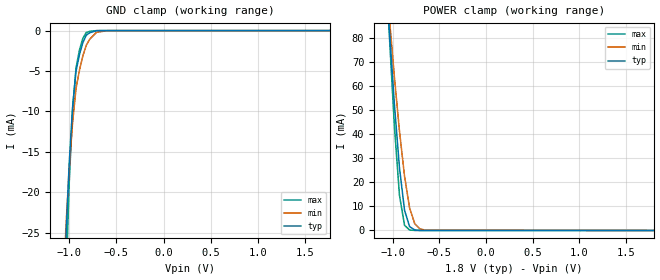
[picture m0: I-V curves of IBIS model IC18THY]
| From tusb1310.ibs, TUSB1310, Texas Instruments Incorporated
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|   Model Cell IC18THY_10P
[Model]   IC18THY
Model_type   Input
Polarity   Non-Inverting
Vinl =  0.63
Vinh =  1.17
C_comp   0.6387869p   0.5449568p   0.7565208p
[Model Spec]
Vinl   0.63   0.567   0.693
Vinh   1.17   1.053   1.287
[Temperature Range]   25   125   -40
[Voltage Range]   1.8   1.62   1.98
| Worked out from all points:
|   GND clamp passes 1 mA (typ) near -0.84 V on its own axis
|   POWER clamp passes 1 mA (typ) near -0.79 V on its own axis
[POWER_clamp]
|   voltage   I(typ)   I(min)   I(max)
-1.8V     607mA      492.8mA    733.5mA
-1.055V   94.75mA    97.21mA    95.13mA
-1.036V   83.56mA    88.51mA    81.22mA
-981.8mV  52.51mA    63.81mA    43.47mA
-927.3mV  26.09mA    41.33mA    14.63mA
-872.7mV  8.397mA    22.47mA    2.133mA
-818.2mV  1.587mA    9.312mA    180.8uA
-763.6mV  228.2uA    2.824mA    13.3uA
-709.1mV  29.94uA    699.1uA    954.3nA
-654.5mV  3.826uA    158.9uA    68.55nA
1.8V      3.537pA    1.237pA    21.97pA
[GND_clamp]
|   voltage   I(typ)   I(min)   I(max)
-1.8V     -539.1mA   -380.2mA   -748.9mA
-1.036V   -26.23mA   -24.68mA   -32.15mA
-1V       -16.52mA   -17.21mA   -19.02mA
-963.6mV  -9.451mA   -11.37mA   -9.842mA
-927.3mV  -5.032mA   -7.151mA   -4.619mA
-890.9mV  -2.977mA   -4.906mA   -2.412mA
-854.5mV  -1.487mA   -3.125mA   -949.1uA
-818.2mV  -563.1uA   -1.808mA   -231uA
-781.8mV  -269.9uA   -1.064mA   -91.31uA
-709.1mV  -19.12uA   -213.6uA   -1.454uA
-600mV    -278.7nA   -13.18uA   -7.254nA
1.764V    3.096pA    114.1pA    9.955pA
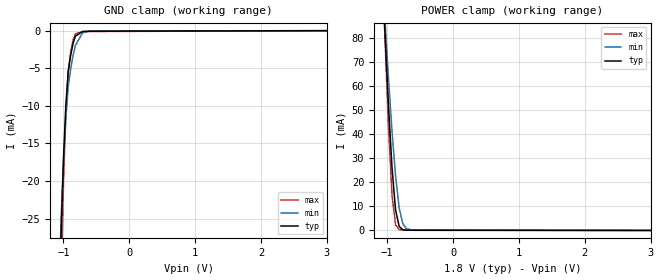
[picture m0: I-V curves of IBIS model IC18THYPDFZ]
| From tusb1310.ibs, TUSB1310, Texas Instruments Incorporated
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|   Model Cell IC18THYPDFZ_PI_10P
[Model]   IC18THYPDFZ
Model_type   Input
Polarity   Non-Inverting
Vinl =  0.63
Vinh =  1.17
C_comp   0.7118224p   0.6198839p   0.831548p
[Model Spec]
Vinl   0.63   0.567   0.693
Vinh   1.17   1.053   1.287
[Temperature Range]   25   125   -40
[Voltage Range]   1.8   1.62   1.98
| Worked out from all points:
|   GND clamp passes 1 mA (typ) near -0.83 V on its own axis
|   POWER clamp passes 1 mA (typ) near -0.79 V on its own axis
[POWER_clamp]
|   voltage   I(typ)   I(min)   I(max)
-1.8V     607.1mA    492.9mA    733.7mA
-1.055V   94.83mA    97.26mA    95.28mA
-1.036V   83.65mA    88.56mA    81.37mA
-981.8mV  52.59mA    63.86mA    43.62mA
-927.3mV  26.18mA    41.37mA    14.78mA
-872.7mV  8.488mA    22.52mA    2.294mA
-818.2mV  1.679mA    9.361mA    343.2uA
-763.6mV  320.4uA    2.873mA    175.7uA
-709.1mV  122uA      748.7uA    163.2uA
-600mV    92.33uA    84.26uA    161.8uA
3.6V      0A         0A         0A
[GND_clamp]
|   voltage   I(typ)   I(min)   I(max)
-1.8V     -542mA     -381.8mA   -757.7mA
-1.073V   -42.86mA   -36.02mA   -57.35mA
-1.036V   -26.92mA   -25.12mA   -33.88mA
-1V       -17.11mA   -17.6mA    -20.43mA
-963.6mV  -9.945mA   -11.71mA   -10.93mA
-927.3mV  -5.429mA   -7.442mA   -5.389mA
-890.9mV  -3.287mA   -5.149mA   -2.924mA
-854.5mV  -1.723mA   -3.323mA   -1.272mA
-818.2mV  -734.7uA   -1.965mA   -433uA
-709.1mV  -120uA     -293uA     -147uA
-600mV    -81.62uA   -66.18uA   -120.1uA
3.6V      0A         0A         0A
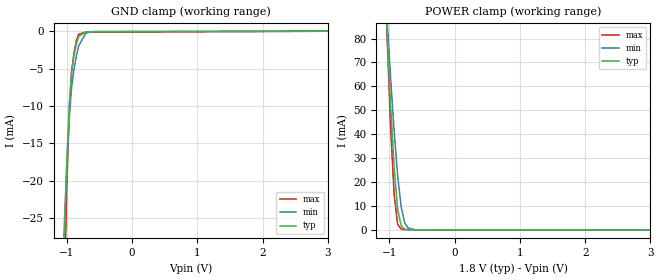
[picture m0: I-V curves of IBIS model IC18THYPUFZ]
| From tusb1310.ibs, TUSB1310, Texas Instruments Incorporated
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|   Model Cell IC18THYPUFZ_PU_1P8
[Model]   IC18THYPUFZ
Model_type   Input
Polarity   Non-Inverting
Vinl =  0.63
Vinh =  1.17
C_comp   0.6359007p   0.5293641p   0.7739418p
[Model Spec]
Vinl   0.63   0.567   0.693
Vinh   1.17   1.053   1.287
[Temperature Range]   25   125   -40
[Voltage Range]   1.8   1.62   1.98
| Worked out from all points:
|   GND clamp passes 1 mA (typ) near -0.83 V on its own axis
|   POWER clamp passes 1 mA (typ) near -0.79 V on its own axis
[POWER_clamp]
|   voltage   I(typ)   I(min)   I(max)
-1.8V     607.5mA    493.2mA    734.2mA
-1.055V   94.9mA     97.36mA    95.3mA
-1.036V   83.71mA    88.66mA    81.38mA
-981.8mV  52.63mA    63.94mA    43.63mA
-927.3mV  26.21mA    41.44mA    14.78mA
-872.7mV  8.503mA    22.57mA    2.281mA
-818.2mV  1.687mA    9.395mA    320.8uA
-763.6mV  321.1uA    2.894mA    143.8uA
-709.1mV  115.9uA    758.6uA    121.8uA
-600mV    72.48uA    81.03uA    101.6uA
3.6V      0A         0A         0A
[GND_clamp]
|   voltage   I(typ)   I(min)   I(max)
-1.8V     -542mA     -381.7mA   -757.7mA
-1.073V   -42.85mA   -36.01mA   -57.34mA
-1.036V   -26.91mA   -25.11mA   -33.87mA
-1V       -17.09mA   -17.59mA   -20.42mA
-963.6mV  -9.93mA    -11.69mA   -10.92mA
-927.3mV  -5.413mA   -7.429mA   -5.37mA
-890.9mV  -3.269mA   -5.135mA   -2.902mA
-854.5mV  -1.703mA   -3.308mA   -1.248mA
-818.2mV  -714uA     -1.949mA   -411uA
-709.1mV  -111.3uA   -277.2uA   -149.7uA
-600mV    -90.19uA   -59.14uA   -147.9uA
3.6V      0A         0A         0A
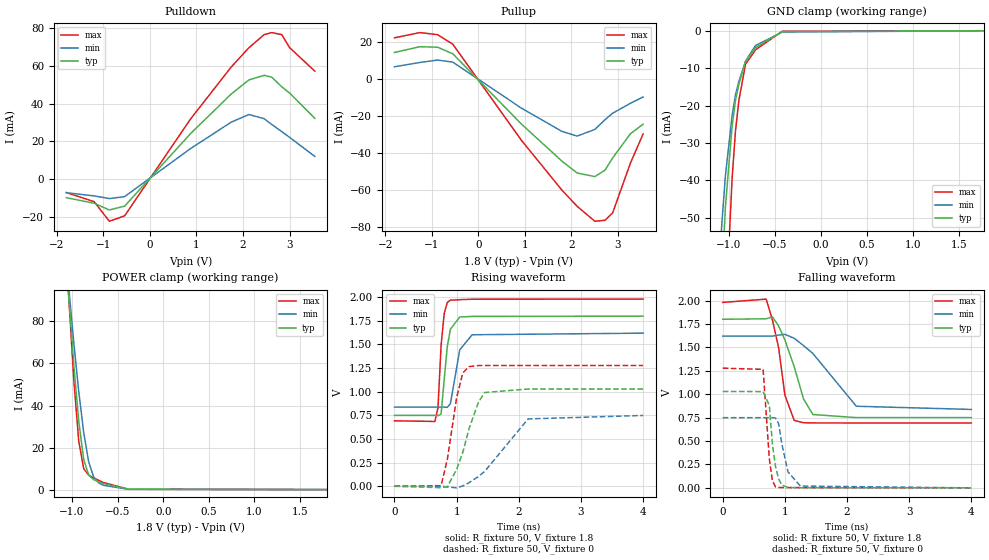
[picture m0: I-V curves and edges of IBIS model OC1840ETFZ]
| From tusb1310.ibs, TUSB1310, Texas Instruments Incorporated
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|   Model Cell OC1840ETFZ
[Model]   OC1840ETFZ
Model_type   3-state
Polarity   Non-Inverting
Enable   Active-Low
Cref =  15.0000pF
Rref =  100.0000M
Vref =  0V
Vmeas =  0.9
C_comp   1.178736p   0.9505015p   1.483028p
[Temperature Range]   25   125   -40
[Voltage Range]   1.8   1.62   1.98
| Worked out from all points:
|   slope of the pulldown table from 0 to 0.27 V, typ, clamps not added: 34.9 ohm
|   slope of the pullup table from 0 to 0.27 V, typ, clamps not added: 36.8 ohm
|   GND clamp passes 1 mA (typ) near -0.52 V on its own axis
|   POWER clamp passes 1 mA (typ) near -0.50 V on its own axis
|   rising waveform, R_fixture 50, V_fixture 1.8: 20-80 % time 103ps typ, 137ps min, 75.2ps max; typ from 0.75 V to 1.8 V
|   rising waveform, R_fixture 50, V_fixture 0: 20-80 % time 298ps typ, 522ps min, 192ps max; typ from 0 V to 1.03 V
|   falling waveform, R_fixture 50, V_fixture 1.8: 20-80 % time 301ps typ, 551ps min, 192ps max; typ from 1.8 V to 0.75 V
|   falling waveform, R_fixture 50, V_fixture 0: 20-80 % time 101ps typ, 146ps min, 86.6ps max; typ from 1.03 V to 0 V
[POWER_clamp]
|   voltage   I(typ)   I(min)   I(max)
-1.8V     632.5mA    513.6mA    762.8mA
-1.055V   103.2mA    104.9mA    105.7mA
-1.036V   91.74mA    95.93mA    91.47mA
-981.8mV  59.9mA     70.34mA    52.88mA
-927.3mV  32.78mA    46.98mA    23.28mA
-872.7mV  14.44mA    27.29mA    9.984mA
-818.2mV  6.921mA    13.34mA    6.938mA
-763.6mV  4.752mA    6.081mA    5.583mA
-709.1mV  3.714mA    3.231mA    4.428mA
-654.5mV  2.886mA    2.042mA    3.366mA
-381.8mV  235.3uA    109.3uA    182.9uA
1.8V      215.7nA    182nA      306.8nA
[Pulldown]
|   voltage   I(typ)   I(min)   I(max)
-1.8V     -9.787mA   -7.157mA   -7.07mA
-1.2V     -12.77mA   -8.858mA   -11.91mA
-872.7mV  -16.33mA   -10.26mA   -22.33mA
-545.5mV  -14.3mA    -9.25mA    -19.44mA
872.7mV   24.19mA    16.25mA    31.94mA
1.745V    45.14mA    30.24mA    59.46mA
2.127V    52.67mA    34.31mA    69.73mA
2.455V    55.09mA    32.1mA     76.69mA
2.618V    54.12mA    29.03mA    77.78mA
2.836V    48.95mA    25.2mA     76.64mA
3V        45.75mA    22.24mA    69.85mA
3.545V    32.26mA    12.07mA    57.29mA
[Pullup]
|   voltage   I(typ)   I(min)   I(max)
-1.8V     14.19mA    6.456mA    22.11mA
-1.255V   17.3mA     8.779mA    24.95mA
-872.7mV  17.03mA    10.1mA     23.81mA
-545.5mV  13.45mA    8.957mA    18.63mA
927.3mV   -24.47mA   -15.88mA   -33.23mA
1.8V      -44.56mA   -28.46mA   -60.23mA
2.127V    -50.96mA   -31.02mA   -68.97mA
2.509V    -52.9mA    -27.4mA    -77.08mA
2.727V    -49.43mA   -22.16mA   -76.51mA
2.891V    -42.81mA   -18.65mA   -72.53mA
3.273V    -29.75mA   -13.28mA   -45.61mA
3.545V    -24.61mA   -9.874mA   -29.89mA
[GND_clamp]
|   voltage   I(typ)   I(min)   I(max)
-1.8V     -615.2mA   -425.7mA   -961.8mA
-1.145V   -108mA     -79.2mA    -177.9mA
-1.109V   -85.62mA   -64.44mA   -141.2mA
-1.073V   -65.28mA   -50.94mA   -107.5mA
-1.036V   -47.02mA   -38.71mA   -76.91mA
-963.6mV  -25.46mA   -22.7mA    -39.54mA
-927.3mV  -18.64mA   -17.14mA   -26.82mA
-890.9mV  -14.38mA   -13.6mA    -18.72mA
-818.2mV  -8.226mA   -8.111mA   -8.937mA
-709.1mV  -4.493mA   -3.908mA   -5.066mA
-418.2mV  -195.3uA   -310.3uA   -95.09uA
1.764V    196.1nA    920.9nA    196.2nA
[Ramp]
| variable   typ   min   max
dV/dt_f  0.6468259/0.3123314n  0.4815675/0.5737224n  0.7935733/0.1960194n
dV/dt_r  0.6319636/0.3084657n  0.4609255/0.5426405n  0.7835253/0.1974173n
R_load = 50
[Rising Waveform]
R_fixture = 50
V_fixture = 1.8
V_fixture_min = 1.62
V_fixture_max = 1.98
| time   V(typ)   V(min)   V(max)
|   time   V(typ)   V(min)   V(max)
0s        749.9mV    837.3mV    692.7mV
650ps     750mV      837.3mV    685.6mV
700ps     747.4mV    837.3mV    831.2mV
750ps     762.5mV    837.4mV    1.493V
800ps     1.129V     837.3mV    1.829V
850ps     1.48V      835.2mV    1.945V
900ps     1.662V     873.7mV    1.969V
1.05ns    1.791V     1.444V     1.974V
1.25ns    1.797V     1.603V     1.979V
4ns       1.8V       1.62V      1.98V
[Rising Waveform]
R_fixture = 50
V_fixture = 0
V_fixture_min = 0
V_fixture_max = 0
| time   V(typ)   V(min)   V(max)
|   time   V(typ)   V(min)   V(max)
0s        629.3nV    577.8nV    735.1nV
750ps     -14.81mV   66.77uV    6.91mV
850ps     -4.371mV   -6.209mV   283.4mV
1ns       178.3mV    -16.88mV   937.8mV
1.1ns     361.4mV    3.417mV    1.2V
1.2ns     610.5mV    37.63mV    1.266V
1.35ns    888.2mV    103.3mV    1.277V
1.45ns    991.8mV    156.5mV    1.278V
2.15ns    1.029V     712.4mV    1.278V
4ns       1.029V     749.3mV    1.278V
[Falling Waveform]
R_fixture = 50
V_fixture = 1.8
V_fixture_min = 1.62
V_fixture_max = 1.98
| time   V(typ)   V(min)   V(max)
|   time   V(typ)   V(min)   V(max)
0s        1.8V       1.62V      1.98V
700ps     1.805V     1.62V      2.015V
800ps     1.826V     1.62V      1.792V
900ps     1.728V     1.631V     1.494V
1ns       1.58V      1.639V     991.6mV
1.15ns    1.294V     1.597V     719.8mV
1.3ns     949.6mV    1.519V     695.9mV
1.45ns    783mV      1.435V     693.3mV
2.15ns    750.1mV    871.3mV    692.7mV
4ns       749.9mV    837.3mV    692.7mV
[Falling Waveform]
R_fixture = 50
V_fixture = 0
V_fixture_min = 0
V_fixture_max = 0
| time   V(typ)   V(min)   V(max)
|   time   V(typ)   V(min)   V(max)
0s        1.029V     749.3mV    1.278V
650ps     1.028V     749.3mV    1.265V
750ps     878.1mV    749.3mV    309.4mV
800ps     463.4mV    749.9mV    75.09mV
850ps     225.4mV    745.6mV    10.35mV
900ps     95.52mV    683.2mV    4.433mV
950ps     30mV       472.5mV    3.749mV
1.05ns    3.802mV    170.9mV    2.715mV
1.25ns    1.892mV    19.19mV    2.607mV
4ns       629.3nV    1.632uV    735.1nV
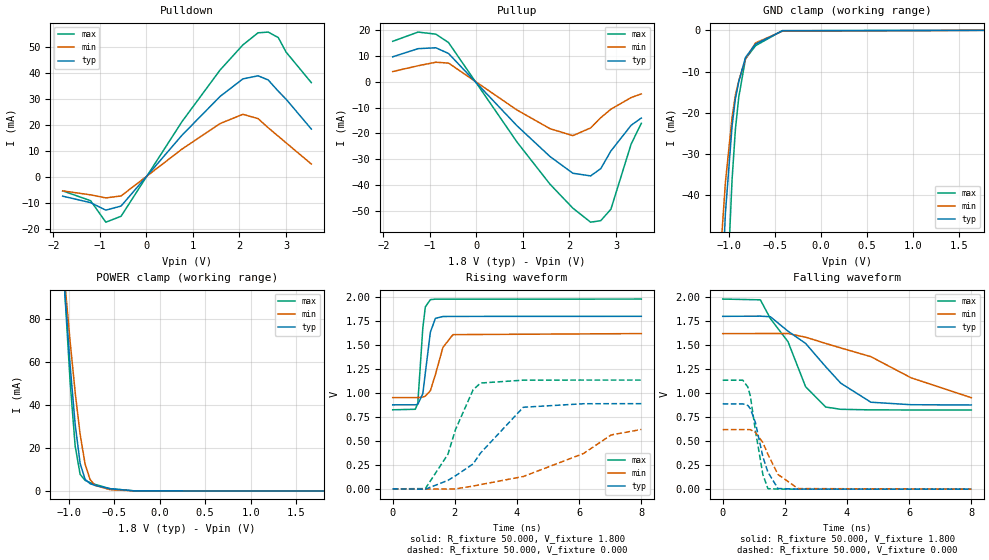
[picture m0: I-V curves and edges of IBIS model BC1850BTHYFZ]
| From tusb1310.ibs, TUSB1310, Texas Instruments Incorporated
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|   Model Cell BC1850BTHYFZ
[Model]   BC1850BTHYFZ
Model_type   I/O
Polarity   Non-Inverting
Enable   Active-Low
Vinl =  0.63
Vinh =  1.17
Cref =  15.0000pF
Rref =  100.0000M
Vref =  0V
Vmeas =  0.9
C_comp   1.209173p   0.9822533p   1.500088p
[Model Spec]
Vinl   0.63   0.567   0.693
Vinh   1.17   1.053   1.287
[Temperature Range]   25   125   -40
[Voltage Range]   1.8   1.62   1.98
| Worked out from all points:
|   slope of the pulldown table from 0 to 0.27 V, typ, clamps not added: 45.7 ohm
|   slope of the pullup table from 0 to 0.27 V, typ, clamps not added: 49.4 ohm
|   GND clamp passes 1 mA (typ) near -0.54 V on its own axis
|   POWER clamp passes 1 mA (typ) near -0.54 V on its own axis
|   rising waveform, R_fixture 50.000, V_fixture 1.800: 20-80 % time 208ps typ, 348ps min, 152ps max; typ from 0.877 V to 1.8 V
|   rising waveform, R_fixture 50.000, V_fixture 0.000: 20-80 % time 1.48ns typ, 2.52ns min, 967ps max; typ from 0 V to 0.889 V
|   falling waveform, R_fixture 50.000, V_fixture 1.800: 20-80 % time 1.78ns typ, 3.17ns min, 1.1ns max; typ from 1.8 V to 0.877 V
|   falling waveform, R_fixture 50.000, V_fixture 0.000: 20-80 % time 417ps typ, 569ps min, 334ps max; typ from 0.889 V to 0 V
[POWER_clamp]
|   voltage   I(typ)   I(min)   I(max)
-1.8V     629.9mA    511.3mA    760mA
-1.055V   101.6mA    103.8mA    103.2mA
-1.036V   90.07mA    94.82mA    89.03mA
-981.8mV  58.22mA    69.3mA     50.5mA
-927.3mV  31.12mA    46.02mA    20.95mA
-872.7mV  12.82mA    26.4mA     7.735mA
-818.2mV  5.391mA    12.51mA    4.922mA
-763.6mV  3.392mA    5.326mA    3.89mA
-709.1mV  2.578mA    2.566mA    3.061mA
-545.5mV  1.007mA    597.1uA    1.066mA
-272.7mV  13.58uA    7.714uA    6.83uA
1.8V      143.8nA    121.3nA    204.6nA
[Pulldown]
|   voltage   I(typ)   I(min)   I(max)
-1.8V     -7.222mA   -5.189mA   -5.194mA
-1.2V     -9.721mA   -6.719mA   -8.965mA
-872.7mV  -12.6mA    -7.897mA   -17.23mA
-545.5mV  -11.02mA   -7.144mA   -14.95mA
763.6mV   16.19mA    10.86mA    21.42mA
1.582V    31.1mA     20.68mA    41.25mA
2.073V    37.87mA    24.25mA    50.93mA
2.4V      39.06mA    22.61mA    55.6mA
2.618V    37.47mA    19.08mA    55.87mA
2.836V    33.11mA    15.81mA    53.74mA
3V        30.12mA    13.33mA    48.23mA
3.545V    18.59mA    5.141mA    36.43mA
[Pullup]
|   voltage   I(typ)   I(min)   I(max)
-1.8V     9.587mA    3.896mA    15.57mA
-1.255V   12.73mA    6.137mA    19.13mA
-872.7mV  13.08mA    7.494mA    18.34mA
-600mV    10.87mA    7.175mA    15.09mA
872.7mV   -17.04mA   -10.95mA   -23.32mA
1.582V    -28.9mA    -18.15mA   -39.58mA
2.073V    -35.35mA   -20.84mA   -48.82mA
2.455V    -36.38mA   -17.86mA   -54.24mA
2.673V    -33.58mA   -13.91mA   -53.65mA
2.891V    -26.76mA   -10.63mA   -49.23mA
3.327V    -16.82mA   -6.13mA    -24.05mA
3.545V    -14.03mA   -4.729mA   -16.07mA
[GND_clamp]
|   voltage   I(typ)   I(min)   I(max)
-1.8V     -608.2mA   -421.4mA   -944.1mA
-1.145V   -104.9mA   -77.06mA   -171.8mA
-1.109V   -82.62mA   -62.41mA   -135.7mA
-1.073V   -62.47mA   -49.03mA   -102.6mA
-1.036V   -44.38mA   -36.91mA   -72.47mA
-963.6mV  -23.17mA   -21.11mA   -36.15mA
-927.3mV  -16.53mA   -15.66mA   -23.93mA
-890.9mV  -12.44mA   -12.23mA   -16.18mA
-818.2mV  -6.58mA    -6.948mA   -6.902mA
-709.1mV  -3.332mA   -3.041mA   -3.731mA
-418.2mV  -133.1uA   -214.3uA   -64.17uA
1.764V    130.9nA    589.6nA    130.9nA
[Ramp]
| variable   typ   min   max
dV/dt_f  0.5550061/1.775344n   0.3868728/3.181701n   0.6941171/1.100787n
dV/dt_r  0.5351995/1.495258n   0.3620258/2.54044n   0.6836041/0.9759474n
R_load = 50
[Rising Waveform]
R_fixture = 50.000
V_fixture = 1.800
V_fixture_min = 1.620
V_fixture_max = 1.980
|  time   V(typ)   V(min)   V(max)
0s        876.6mV    952.2mV    825mV
727.3ps   876.7mV    952.2mV    830.2mV
808.1ps   882.2mV    952.8mV    894mV
969.7ps   993.6mV    957.2mV    1.682V
1.051ns   1.212V     968.3mV    1.899V
1.212ns   1.635V     1.024V     1.974V
1.374ns   1.779V     1.192V     1.979V
1.616ns   1.798V     1.476V     1.979V
1.939ns   1.799V     1.609V     1.979V
8ns       1.8V       1.62V      1.98V
[Rising Waveform]
R_fixture = 50.000
V_fixture = 0.000
V_fixture_min = 0.000
V_fixture_max = 0.000
|  time   V(typ)   V(min)   V(max)
0s        526nV      -2.92uV    624nV
1.051ns   -3.142mV   -1.85mV    2.951mV
1.778ns   88.51mV    -1.953mV   361.8mV
2.02ns    136.3mV    168.4uV    618.4mV
2.586ns   260.1mV    28.78mV    1.033V
2.828ns   374.4mV    44.49mV    1.104V
4.202ns   851.4mV    128.9mV    1.134V
6.141ns   888.1mV    369.1mV    1.135V
7.03ns    888.6mV    562.6mV    1.135V
8ns       888.7mV    619.7mV    1.135V
[Falling Waveform]
R_fixture = 50.000
V_fixture = 1.800
V_fixture_min = 1.620
V_fixture_max = 1.980
|  time   V(typ)   V(min)   V(max)
0s        1.8V       1.62V      1.98V
1.212ns   1.802V     1.621V     1.972V
1.535ns   1.796V     1.621V     1.776V
2.101ns   1.645V     1.621V     1.536V
2.667ns   1.518V     1.583V     1.067V
3.313ns   1.276V     1.518V     855.5mV
3.798ns   1.104V     1.471V     831.8mV
4.768ns   905.6mV    1.38V      825.8mV
6.061ns   879.6mV    1.16V      825mV
8ns       876.8mV    952.8mV    825mV
[Falling Waveform]
R_fixture = 50.000
V_fixture = 0.000
V_fixture_min = 0.000
V_fixture_max = 0.000
|  time   V(typ)   V(min)   V(max)
0s        888.7mV    620.2mV    1.135V
646.5ps   888.6mV    620.2mV    1.135V
808.1ps   872.1mV    620.1mV    1.064V
888.9ps   837.9mV    619.8mV    970.7mV
1.051ns   695.8mV    591.9mV    612.2mV
1.293ns   337mV      485.2mV    152.2mV
1.455ns   176.9mV    363.8mV    5.258mV
1.778ns   6.868mV    153.4mV    491.3uV
2.424ns   310.3uV    6.05mV     589.1uV
8ns       8.704uV    315.9uV    722.4nV
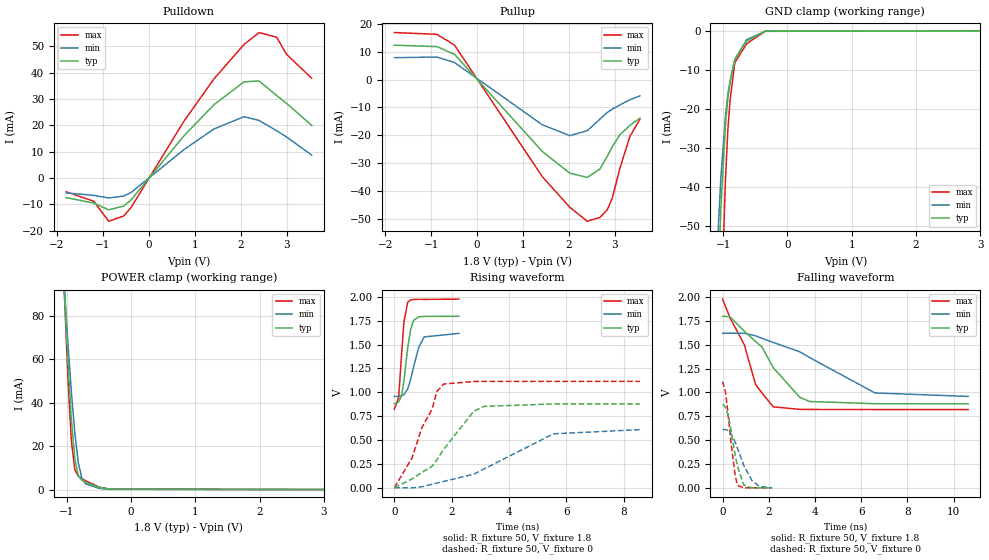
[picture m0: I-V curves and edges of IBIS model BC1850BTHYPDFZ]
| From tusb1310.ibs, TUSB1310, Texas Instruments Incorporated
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|   Model Cell BC1850BTHYPDFZ
[Model]   BC1850BTHYPDFZ
Model_type   I/O
Polarity   Non-Inverting
Enable   Active-Low
Vinl =  0.63
Vinh =  1.17
Cref =  15pF
Rref =  100.00M
Vref =  0V
Vmeas =  0.9
C_comp   1.283935p   1.060071p   1.576138p
[Model Spec]
Vinl   0.63   0.567   0.693
Vinh   1.17   1.053   1.287
[Temperature Range]   25   125   -40
[Voltage Range]   1.8   1.62   1.98
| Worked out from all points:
|   slope of the pulldown table from 0 to 0.27 V, typ, clamps not added: 46.2 ohm
|   slope of the pullup table from 0 to 0.27 V, typ, clamps not added: 49.9 ohm
|   GND clamp passes 1 mA (typ) near -0.51 V on its own axis
|   POWER clamp passes 1 mA (typ) near -0.49 V on its own axis
|   rising waveform, R_fixture 50, V_fixture 1.8: 20-80 % time 227ps typ, 342ps min, 157ps max; typ from 0.881 V to 1.8 V
|   rising waveform, R_fixture 50, V_fixture 0: 20-80 % time 1.49ns typ, 2.37ns min, 996ps max; typ from 0 V to 0.878 V
|   falling waveform, R_fixture 50, V_fixture 1.8: 20-80 % time 1.85ns typ, 3.2ns min, 1.1ns max; typ from 1.8 V to 0.881 V
|   falling waveform, R_fixture 50, V_fixture 0: 20-80 % time 403ps typ, 607ps min, 308ps max; typ from 0.878 V to 0.001 V
[POWER_clamp]
|   voltage   I(typ)   I(min)   I(max)
-1.8V     626.8mA    507.5mA    757.3mA
-1.055V   102.5mA    102.2mA    104.7mA
-1.036V   91.05mA    93.34mA    90.54mA
-981.8mV  59.28mA    68.12mA    51.96mA
-927.3mV  32.2mA     45.14mA    22.37mA
-872.7mV  13.88mA    25.81mA    9.114mA
-818.2mV  6.394mA    12.19mA    6.211mA
-763.6mV  4.307mA    5.255mA    5.068mA
-709.1mV  3.392mA    2.68mA     4.114mA
-490.9mV  1.001mA    514.4uA    1.059mA
-327.3mV  185.5uA    83.82uA    224.6uA
3.6V      0A         0A         0A
[Pulldown]
|   voltage   I(typ)   I(min)   I(max)
-1.8V     -7.492mA   -5.724mA   -5.291mA
-1.2V     -9.558mA   -6.628mA   -8.851mA
-872.7mV  -12.15mA   -7.636mA   -16.5mA
-545.5mV  -10.68mA   -6.908mA   -14.45mA
-381.8mV  -8.289mA   -5.489mA   -11.15mA
763.6mV   15.97mA    10.73mA    21.5mA
1.418V    27.81mA    18.58mA    37.63mA
2.073V    36.5mA     23.27mA    50.73mA
2.4V      36.84mA    21.84mA    55.23mA
2.782V    31.32mA    17.92mA    53.44mA
3V        28.29mA    15.52mA    46.92mA
3.545V    19.95mA    8.656mA    37.88mA
[Pullup]
|   voltage   I(typ)   I(min)   I(max)
-1.8V     12.28mA    7.815mA    16.8mA
-872.7mV  11.77mA    8.042mA    16.18mA
-490.9mV  9.018mA    6.084mA    12.33mA
1.418V    -25.71mA   -16.17mA   -34.71mA
2.018V    -33.5mA    -20.09mA   -45.72mA
2.4V      -35.05mA   -18.32mA   -50.74mA
2.673V    -32.04mA   -14.18mA   -49.35mA
2.836V    -27.45mA   -11.76mA   -46.61mA
2.945V    -23.99mA   -10.6mA    -42.36mA
3.109V    -19.72mA   -9.094mA   -31.78mA
3.327V    -16.43mA   -7.235mA   -20.38mA
3.545V    -13.81mA   -5.864mA   -14.2mA
[GND_clamp]
|   voltage   I(typ)   I(min)   I(max)
-1.8V     -610.8mA   -422.6mA   -952.5mA
-1.145V   -106mA     -77.87mA   -174.7mA
-1.109V   -83.72mA   -63.18mA   -138.3mA
-1.073V   -63.5mA    -49.76mA   -105mA
-1.036V   -45.35mA   -37.61mA   -74.63mA
-963.6mV  -24.01mA   -21.73mA   -37.86mA
-927.3mV  -17.3mA    -16.24mA   -25.44mA
-890.9mV  -13.14mA   -12.77mA   -17.57mA
-818.2mV  -7.189mA   -7.419mA   -8.136mA
-636.4mV  -2.646mA   -2.252mA   -3.335mA
-345.5mV  -90.7uA    -126.8uA   -93.09uA
3.6V      0A         0A         0A
|   18.18182m   2.201233u   1.33167u   3.377792u
|   54.54545m   6.627192u   4.033074u   10.15232u
|   90.90909m   10.9116u   6.628331u   16.74859u
|   0.1272727   15.12342u   9.170934u   23.25348u
|   0.1636364   19.26266u   11.66088u   29.66699u
|   0.2   23.25281u   14.04341u   35.89293u
|   0.2363636   27.16634u   16.37083u   42.02251u
|   0.2727273   31.00325u   18.64315u   48.05572u
|   0.3090909   34.68251u   20.80219u   53.89073u
|   0.3454545   38.28061u   22.90299u   59.62373u
|   0.3818182   41.79757u   24.94553u   65.25471u
|   0.4181818   45.14731u   26.86818u   70.67549u
|   0.4545455   48.41086u   28.7291u   75.98789u
|   0.4909091   51.58823u   30.52831u   81.19192u
|   0.5272727   54.58777u   32.20039u   86.17228u
|   0.5636364   57.49556u   33.80702u   91.03716u
|   0.6   60.31158u   35.34818u   95.78655u
|   0.6363636   62.93814u   36.75461u   0.1002972m
|   0.6727273   65.46691u   38.09181u   0.1046845m
|   0.7090909   67.89787u   39.35977u   0.1089484m
|   0.7454545   70.12702u   40.48589u   0.112957m
|   0.7818182   72.25219u   41.53981u   0.1168336m
|   0.8181818   74.27341u   42.52152u   0.120578m
|   0.8545455   76.08106u   43.35788u   0.1240492m
|   0.8909091   77.77967u   44.12253u   0.1273792m
|   0.9272727   79.36924u   44.81549u   0.1305681m
|   0.9636364   80.73845u   45.37169u   0.1334657m
|   1   81.99831u   45.86605u   0.1362137m
|   1.036364   83.14882u   46.29856u   0.1388121m
|   1.072727   84.08863u   46.6271u   0.1411052m
|   1.109091   84.93147u   46.91555u   0.1432444m
|   1.145455   85.67734u   47.16391u   0.1452296m
|   1.181818   86.25574u   47.35531u   0.1469103m
|   1.218182   86.76719u   47.52761u   0.1484449m
|   1.254545   87.21169u   47.68083u   0.1498333m
|   1.290909   87.55717u   47.80909u   0.1509534m
|   1.327273   87.8682u   47.92913u   0.1519575m
|   1.363636   88.14478u   48.04095u   0.1528456m
|   1.4   88.37503u   48.1416u   0.1535465m
|   1.436364   88.58974u   48.23829u   0.1541769m
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[Ramp]
| variable   typ   min   max
dV/dt_f   0.550795/1.858579n   0.3980642/3.215319n   0.694743/1.105469n
dV/dt_r  0.5289953/1.505573n   0.3676038/2.39061n   0.6713161/1.005495n
R_load = 50
[Rising Waveform]
R_fixture = 50
V_fixture = 1.8
V_fixture_min = 1.62
V_fixture_max = 1.98
|   time   V(typ)   V(min)   V(max)
0s        881.4mV    956.3mV    820.7mV
152ps     899.3mV    956.6mV    948.3mV
256ps     967.6mV    962.8mV    1.416V
336ps     1.122V     977.5mV    1.738V
466ps     1.465V     1.034V     1.943V
568ps     1.658V     1.134V     1.968V
668ps     1.753V     1.262V     1.972V
850ps     1.791V     1.47V      1.974V
1.04ns    1.795V     1.58V      1.973V
2.256ns   1.796V     1.617V     1.976V
[Rising Waveform]
R_fixture = 50
V_fixture = 0
V_fixture_min = 0
V_fixture_max = 0
|   time   V(typ)   V(min)   V(max)
0s        74.93nV    142.1nV    53.71nV
614ps     90.88mV    -1.962mV   309.2mV
964ps     160.4mV    9.986mV    631.9mV
1.312ns   222.7mV    36.15mV    819.5mV
1.486ns   292.4mV    49.22mV    1.009V
1.72ns    401.8mV    65.07mV    1.086V
2.776ns   803.3mV    141.6mV    1.113V
3.138ns   851.9mV    197.9mV    1.114V
5.556ns   877.7mV    564.6mV    1.114V
8.568ns   877.8mV    608.3mV    1.114V
[Falling Waveform]
R_fixture = 50
V_fixture = 1.8
V_fixture_min = 1.62
V_fixture_max = 1.98
|   time   V(typ)   V(min)   V(max)
0s        1.798V     1.619V     1.977V
324ps     1.792V     1.62V      1.78V
940ps     1.641V     1.619V     1.499V
1.43ns    1.533V     1.593V     1.083V
1.704ns   1.476V     1.566V     994mV
2.196ns   1.259V     1.523V     848.8mV
3.336ns   949.8mV    1.426V     822.5mV
3.768ns   904.9mV    1.365V     821.4mV
6.596ns   881.7mV    994.3mV    820.7mV
10.63ns   881.4mV    958mV      820.7mV
[Falling Waveform]
R_fixture = 50
V_fixture = 0
V_fixture_min = 0
V_fixture_max = 0
|   time   V(typ)   V(min)   V(max)
0s        877.8mV    609.9mV    1.114V
128ps     842.8mV    610.3mV    1.003V
258ps     746.5mV    600mV      729.9mV
366ps     604.3mV    568.1mV    472.6mV
536ps     352.5mV    484.9mV    148.4mV
636ps     232.2mV    421.2mV    28.01mV
916ps     30.61mV    236.2mV    975.7uV
1.262ns   1.129mV    80.37mV    835.8uV
1.596ns   387.9uV    14.93mV    902.5uV
2.142ns   575.3uV    1.642mV    408.1uV
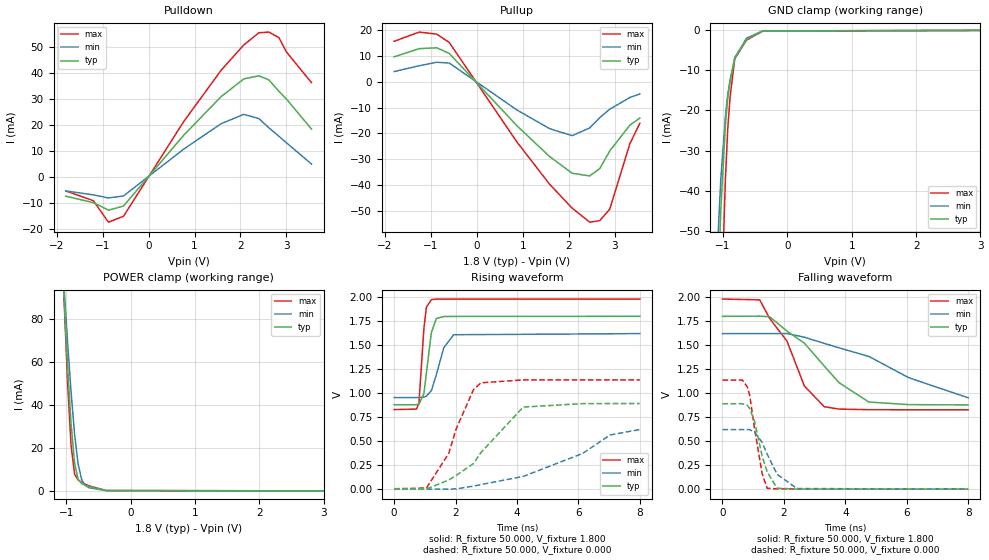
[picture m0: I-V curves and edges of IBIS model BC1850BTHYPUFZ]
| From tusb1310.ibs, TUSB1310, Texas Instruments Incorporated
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|   Model Cell C1850BTHYPUFZ_PU_1P8
[Model]   BC1850BTHYPUFZ
Model_type   I/O
Polarity   Non-Inverting
Enable   Active-Low
Vinl =  0.63
Vinh =  1.17
Cref =  15.0000pF
Rref =  100.0000M
Vref =  0V
Vmeas =  0.9
C_comp   1.239458p   1.004824p   1.546887p
[Model Spec]
Vinl   0.63   0.567   0.693
Vinh   1.17   1.053   1.287
[Temperature Range]   25   125   -40
[Voltage Range]   1.8   1.62   1.98
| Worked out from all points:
|   slope of the pulldown table from 0 to 0.27 V, typ, clamps not added: 45.7 ohm
|   slope of the pullup table from 0 to 0.27 V, typ, clamps not added: 49.4 ohm
|   GND clamp passes 1 mA (typ) near -0.54 V on its own axis
|   POWER clamp passes 1 mA (typ) near -0.54 V on its own axis
|   rising waveform, R_fixture 50.000, V_fixture 1.800: 20-80 % time 210ps typ, 350ps min, 153ps max; typ from 0.878 V to 1.8 V
|   rising waveform, R_fixture 50.000, V_fixture 0.000: 20-80 % time 1.5ns typ, 2.54ns min, 977ps max; typ from 0.002 V to 0.891 V
|   falling waveform, R_fixture 50.000, V_fixture 1.800: 20-80 % time 1.78ns typ, 3.17ns min, 1.11ns max; typ from 1.8 V to 0.879 V
|   falling waveform, R_fixture 50.000, V_fixture 0.000: 20-80 % time 419ps typ, 571ps min, 336ps max; typ from 0.891 V to 0.002 V
[POWER_clamp]
|   voltage   I(typ)   I(min)   I(max)
-1.8V     630.5mA    511.7mA    760.7mA
-1.055V   101.7mA    104mA      103.4mA
-1.036V   90.22mA    94.97mA    89.19mA
-981.8mV  58.34mA    69.43mA    50.65mA
-927.3mV  31.23mA    46.13mA    21.1mA
-872.7mV  12.92mA    26.49mA    7.884mA
-818.2mV  5.491mA    12.59mA    5.062mA
-763.6mV  3.485mA    5.395mA    4.02mA
-709.1mV  2.664mA    2.626mA    3.181mA
-654.5mV  2.059mA    1.546mA    2.418mA
-381.8mV  196.6uA    98.24uA    180.9uA
3.6V      0A         0A         0A
[Pulldown]
|   voltage   I(typ)   I(min)   I(max)
-1.8V     -7.221mA   -5.188mA   -5.193mA
-1.2V     -9.719mA   -6.718mA   -8.96mA
-872.7mV  -12.6mA    -7.896mA   -17.22mA
-545.5mV  -11.02mA   -7.144mA   -14.95mA
763.6mV   16.19mA    10.86mA    21.42mA
1.582V    31.1mA     20.68mA    41.25mA
2.073V    37.87mA    24.25mA    50.93mA
2.4V      39.06mA    22.61mA    55.6mA
2.618V    37.47mA    19.08mA    55.87mA
2.836V    33.11mA    15.81mA    53.74mA
3V        30.12mA    13.33mA    48.23mA
3.545V    18.59mA    5.142mA    36.43mA
[Pullup]
|   voltage   I(typ)   I(min)   I(max)
-1.8V     9.587mA    3.896mA    15.57mA
-1.255V   12.73mA    6.137mA    19.13mA
-872.7mV  13.08mA    7.494mA    18.34mA
-600mV    10.87mA    7.174mA    15.09mA
872.7mV   -17.04mA   -10.95mA   -23.32mA
1.582V    -28.9mA    -18.15mA   -39.58mA
2.073V    -35.35mA   -20.84mA   -48.82mA
2.455V    -36.38mA   -17.86mA   -54.24mA
2.673V    -33.57mA   -13.9mA    -53.65mA
2.891V    -26.75mA   -10.62mA   -49.2mA
3.327V    -16.82mA   -6.13mA    -24.05mA
3.545V    -14.03mA   -4.729mA   -16.07mA
[GND_clamp]
|   voltage   I(typ)   I(min)   I(max)
-1.8V     -611mA     -422.9mA   -952.5mA
-1.145V   -105.8mA   -77.64mA   -174.4mA
-1.109V   -83.48mA   -62.94mA   -137.9mA
-1.073V   -63.23mA   -49.5mA    -104.5mA
-1.036V   -45.05mA   -37.34mA   -74.12mA
-963.6mV  -23.65mA   -21.44mA   -37.18mA
-927.3mV  -16.91mA   -15.94mA   -24.65mA
-890.9mV  -12.72mA   -12.46mA   -16.66mA
-818.2mV  -6.73mA    -7.089mA   -7.08mA
-636.4mV  -2.27mA    -1.959mA   -2.463mA
-381.8mV  -137.2uA   -150.6uA   -163uA
3.6V      0A         0A         0A
[Ramp]
| variable   typ   min   max
dV/dt_f  0.5538634/1.783662n   0.3857433/3.187523n   0.6924353/1.105464n
dV/dt_r  0.5349039/1.508351n   0.3620655/2.556431n   0.6830903/0.9848547n
R_load = 50
[Rising Waveform]
R_fixture = 50.000
V_fixture = 1.800
V_fixture_min = 1.620
V_fixture_max = 1.980
|  time   V(typ)   V(min)   V(max)
0s        878.5mV    953.3mV    827.8mV
727.3ps   878.6mV    953.3mV    833mV
808.1ps   884mV      953.8mV    896.2mV
969.7ps   994.1mV    958.2mV    1.677V
1.051ns   1.21V      969.3mV    1.896V
1.212ns   1.631V     1.025V     1.974V
1.374ns   1.778V     1.19V      1.979V
1.616ns   1.798V     1.473V     1.979V
1.939ns   1.799V     1.608V     1.979V
8ns       1.8V       1.62V      1.98V
[Rising Waveform]
R_fixture = 50.000
V_fixture = 0.000
V_fixture_min = 0.000
V_fixture_max = 0.000
|  time   V(typ)   V(min)   V(max)
0s        2.104mV    -3.051uV   2.952mV
1.051ns   -842.2uV   -1.827mV   9.715mV
1.778ns   93.73mV    -1.295mV   371.2mV
2.02ns    141.7mV    1.169mV    626.4mV
2.586ns   266.4mV    30.22mV    1.037V
2.828ns   380.4mV    45.97mV    1.107V
4.202ns   853.8mV    130.9mV    1.137V
6.141ns   890.1mV    370.9mV    1.137V
7.03ns    890.6mV    563.2mV    1.137V
8ns       890.6mV    619.7mV    1.137V
[Falling Waveform]
R_fixture = 50.000
V_fixture = 1.800
V_fixture_min = 1.620
V_fixture_max = 1.980
|  time   V(typ)   V(min)   V(max)
0s        1.8V       1.62V      1.98V
1.212ns   1.802V     1.621V     1.972V
1.535ns   1.796V     1.621V     1.779V
2.101ns   1.647V     1.621V     1.542V
2.667ns   1.521V     1.583V     1.075V
3.313ns   1.283V     1.519V     859.8mV
3.798ns   1.109V     1.472V     834.8mV
4.768ns   908.6mV    1.383V     828.7mV
6.061ns   881.6mV    1.162V     827.8mV
8ns       878.7mV    952.8mV    827.8mV
[Falling Waveform]
R_fixture = 50.000
V_fixture = 0.000
V_fixture_min = 0.000
V_fixture_max = 0.000
|  time   V(typ)   V(min)   V(max)
0s        890.6mV    621.6mV    1.137V
646.5ps   890.5mV    621.6mV    1.137V
808.1ps   874.1mV    621.5mV    1.067V
888.9ps   840.3mV    621.1mV    974.6mV
1.051ns   699.3mV    593.4mV    619.2mV
1.293ns   342.1mV    487.3mV    161.1mV
1.455ns   181.8mV    366.4mV    10.77mV
1.778ns   11.18mV    156.3mV    4.77mV
2.424ns   3.238mV    8.463mV    4.093mV
8ns       2.113mV    1.61mV     2.952mV
